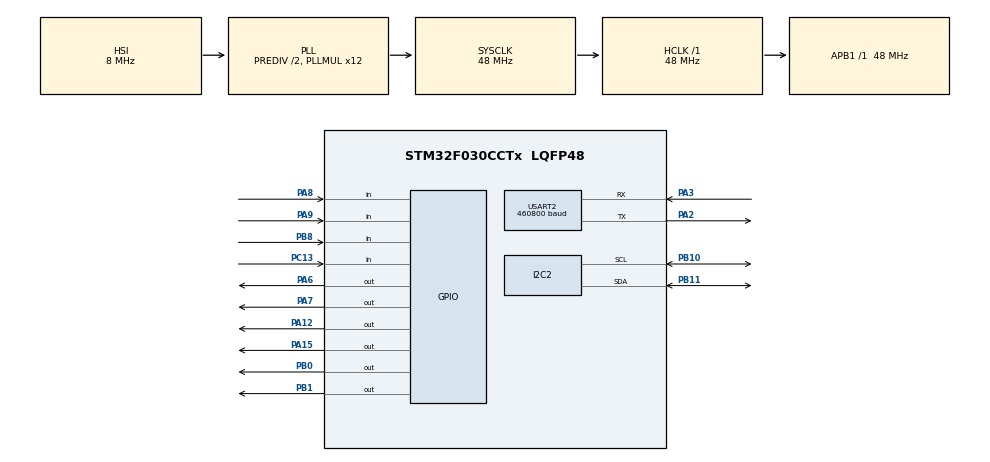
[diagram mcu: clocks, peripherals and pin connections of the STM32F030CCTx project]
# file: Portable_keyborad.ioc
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Dma.I2C2_RX.0.Direction=DMA_PERIPH_TO_MEMORY
Dma.I2C2_RX.0.Instance=DMA1_Channel5
Dma.I2C2_RX.0.MemDataAlignment=DMA_MDATAALIGN_BYTE
Dma.I2C2_RX.0.MemInc=DMA_MINC_ENABLE
Dma.I2C2_RX.0.Mode=DMA_NORMAL
Dma.I2C2_RX.0.PeriphDataAlignment=DMA_PDATAALIGN_BYTE
Dma.I2C2_RX.0.PeriphInc=DMA_PINC_DISABLE
Dma.I2C2_RX.0.Priority=DMA_PRIORITY_LOW
Dma.I2C2_TX.1.Direction=DMA_MEMORY_TO_PERIPH
Dma.I2C2_TX.1.Instance=DMA1_Channel4
Dma.I2C2_TX.1.MemDataAlignment=DMA_MDATAALIGN_BYTE
Dma.I2C2_TX.1.MemInc=DMA_MINC_ENABLE
Dma.I2C2_TX.1.Mode=DMA_NORMAL
Dma.I2C2_TX.1.PeriphDataAlignment=DMA_PDATAALIGN_BYTE
Dma.I2C2_TX.1.PeriphInc=DMA_PINC_DISABLE
Dma.I2C2_TX.1.Priority=DMA_PRIORITY_LOW
Dma.Request0=I2C2_RX
Dma.Request1=I2C2_TX
FREERTOS.Tasks01=defaultTask,0,128,StartDefaultTask,Default,NULL
I2C2.Timing=0x20303E5D
IWDG.Prescaler=IWDG_PRESCALER_32
IWDG.Reload=2000
IWDG.Window=2000
Mcu.Family=STM32F0
Mcu.Name=STM32F030CCTx
Mcu.Package=LQFP48
NVIC.DMA1_Channel4_5_IRQn=true\:3\:0\:false\:false\:true\:true\:false
NVIC.TIM1_BRK_UP_TRG_COM_IRQn=true\:3\:0\:false\:false\:true\:true\:true
PA12.Signal=GPIO_Output
PA13.Mode=Serial_Wire
PA13.Signal=SYS_SWDIO
PA14.Mode=Serial_Wire
PA14.Signal=SYS_SWCLK
PA15.Signal=GPIO_Output
PA2.Mode=Asynchronous
PA2.Signal=USART2_TX
PA3.Mode=Asynchronous
PA3.Signal=USART2_RX
PA6.Signal=GPIO_Output
PA7.Signal=GPIO_Output
PA8.GPIO_PuPd=GPIO_PULLUP
PA8.Signal=GPIO_Input
PA9.GPIO_PuPd=GPIO_PULLUP
PA9.Signal=GPIO_Input
PB0.Signal=GPIO_Output
PB1.Signal=GPIO_Output
PB10.Mode=I2C
PB10.Signal=I2C2_SCL
PB11.Mode=I2C
PB11.Signal=I2C2_SDA
PB8.Signal=GPIO_Input
PC13.GPIO_PuPd=GPIO_PULLUP
PC13.Signal=GPIO_Input
PC14OSC32_IN.GPIO_PuPd=GPIO_PULLUP
PC14OSC32_IN.Signal=GPIO_Input
PC15OSC32_OUT.GPIO_PuPd=GPIO_PULLUP
PC15OSC32_OUT.Signal=GPIO_Input
ProjectManager.HeapSize=0x200
ProjectManager.StackSize=0x400
ProjectManager.TargetToolchain=MDK-ARM V5
RCC.AHBFreq_Value=48000000
RCC.APB1Freq_Value=48000000
RCC.APB1TimFreq_Value=48000000
RCC.HCLKFreq_Value=48000000
RCC.HSE_VALUE=12000000
RCC.PLLDivider=RCC_PREDIV_DIV2
RCC.PLLMUL=RCC_PLL_MUL12
RCC.SYSCLKFreq_VALUE=48000000
RCC.SYSCLKSource=RCC_SYSCLKSOURCE_PLLCLK
TIM1.Period=100-1
TIM1.Prescaler=480
USART2.BaudRate=460800
USART2.VirtualMode-Asynchronous=VM_ASYNC
VP_FREERTOS_VS_ENABLE.Mode=Enabled
VP_IWDG_VS_IWDG.Mode=IWDG_Activate
VP_TIM1_VS_ClockSourceINT.Mode=Internal
board=custom

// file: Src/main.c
/* USER CODE BEGIN Header */
/**
  ******************************************************************************
  * @file           : main.c
  * @brief          : Main program body
  ******************************************************************************
  * This notice applies to any and all portions of this file
  * that are not between comment pairs USER CODE BEGIN and
  * USER CODE END. Other portions of this file, whether
  * inserted by the user or by software development tools
  * are owned by their respective copyright owners.
  *
  * Copyright (c) 2019 STMicroelectronics International N.V.
  * All rights reserved.
  *
  * Redistribution and use in source and binary forms, with or without
  * modification, are permitted, provided that the following conditions are met:
  *
  * 1. Redistribution of source code must retain the above copyright notice,
  *    this list of conditions and the following disclaimer.
  * 2. Redistributions in binary form must reproduce the above copyright notice,
  *    this list of conditions and the following disclaimer in the documentation
  *    and/or other materials provided with the distribution.
  * 3. Neither the name of STMicroelectronics nor the names of other
  *    contributors to this software may be used to endorse or promote products
  *    derived from this software without specific written permission.
  * 4. This software, including modifications and/or derivative works of this
  *    software, must execute solely and exclusively on microcontroller or
  *    microprocessor devices manufactured by or for STMicroelectronics.
  * 5. Redistribution and use of this software other than as permitted under
  *    this license is void and will automatically terminate your rights under
  *    this license.
  *
  * THIS SOFTWARE IS PROVIDED BY STMICROELECTRONICS AND CONTRIBUTORS "AS IS"
  * AND ANY EXPRESS, IMPLIED OR STATUTORY WARRANTIES, INCLUDING, BUT NOT
  * LIMITED TO, THE IMPLIED WARRANTIES OF MERCHANTABILITY, FITNESS FOR A
  * PARTICULAR PURPOSE AND NON-INFRINGEMENT OF THIRD PARTY INTELLECTUAL PROPERTY
  * RIGHTS ARE DISCLAIMED TO THE FULLEST EXTENT PERMITTED BY LAW. IN NO EVENT
  * SHALL STMICROELECTRONICS OR CONTRIBUTORS BE LIABLE FOR ANY DIRECT, INDIRECT,
  * INCIDENTAL, SPECIAL, EXEMPLARY, OR CONSEQUENTIAL DAMAGES (INCLUDING, BUT NOT
  * LIMITED TO, PROCUREMENT OF SUBSTITUTE GOODS OR SERVICES; LOSS OF USE, DATA,
  * OR PROFITS; OR BUSINESS INTERRUPTION) HOWEVER CAUSED AND ON ANY THEORY OF
  * LIABILITY, WHETHER IN CONTRACT, STRICT LIABILITY, OR TORT (INCLUDING
  * NEGLIGENCE OR OTHERWISE) ARISING IN ANY WAY OUT OF THE USE OF THIS SOFTWARE,
  * EVEN IF ADVISED OF THE POSSIBILITY OF SUCH DAMAGE.
  *
  ******************************************************************************
  */
/* USER CODE END Header */

#include "main.h"
#include "cmsis_os.h"

/* USER CODE BEGIN Includes */
#include "task_manager.h"
#include "dev_manager.h"
#include "includes.h"
#include "board.h"
#include "main_task.h"
#include "led.h"
/* USER CODE END Includes */

I2C_HandleTypeDef hi2c2;
DMA_HandleTypeDef hdma_i2c2_rx;
DMA_HandleTypeDef hdma_i2c2_tx;

IWDG_HandleTypeDef hiwdg;

TIM_HandleTypeDef htim1;

UART_HandleTypeDef huart2;

osThreadId defaultTaskHandle;

void SystemClock_Config(void);
static void MX_GPIO_Init(void);
static void MX_DMA_Init(void);
static void MX_USART2_UART_Init(void);
static void MX_I2C2_Init(void);
static void MX_TIM1_Init(void);
static void MX_IWDG_Init(void);
void StartDefaultTask(void const * argument);

/* USER CODE BEGIN PFP */
extern u8  get_cpu_reset_source(void);
extern void board_printf_sys_information(void);
/* USER CODE END PFP */

int main(void)
{

  /* MCU Configuration--------------------------------------------------------*/

  /* Reset of all peripherals, Initializes the Flash interface and the Systick. */
  HAL_Init();

  /* Configure the system clock */
  SystemClock_Config();

  /* Initialize all configured peripherals */
  MX_GPIO_Init();
  MX_DMA_Init();
  MX_USART2_UART_Init();
  MX_I2C2_Init();
  MX_TIM1_Init();
  MX_IWDG_Init();
  /* USER CODE BEGIN 2 */

  board_printf_sys_information();

	main_task_init(NULL);

  /* USER CODE END 2 */

  /* Create the thread(s) */
  /* definition and creation of defaultTask */
  osThreadDef(defaultTask, StartDefaultTask, osPriorityNormal, 0, 32);
  defaultTaskHandle = osThreadCreate(osThread(defaultTask), NULL);

  /* Start scheduler */
  osKernelStart();

  /* We should never get here as control is now taken by the scheduler */

  /* Infinite loop */
  while (1)
  {

  }
}

void SystemClock_Config(void)
{
  RCC_OscInitTypeDef RCC_OscInitStruct = {0};
  RCC_ClkInitTypeDef RCC_ClkInitStruct = {0};

  /**Initializes the CPU, AHB and APB busses clocks
  */
  RCC_OscInitStruct.OscillatorType = RCC_OSCILLATORTYPE_HSI|RCC_OSCILLATORTYPE_LSI;
  RCC_OscInitStruct.HSIState = RCC_HSI_ON;
  RCC_OscInitStruct.HSICalibrationValue = RCC_HSICALIBRATION_DEFAULT;
  RCC_OscInitStruct.LSIState = RCC_LSI_ON;
  RCC_OscInitStruct.PLL.PLLState = RCC_PLL_ON;
  RCC_OscInitStruct.PLL.PLLSource = RCC_PLLSOURCE_HSI;
  RCC_OscInitStruct.PLL.PLLMUL = RCC_PLL_MUL12;
  RCC_OscInitStruct.PLL.PREDIV = RCC_PREDIV_DIV2;
  if (HAL_RCC_OscConfig(&RCC_OscInitStruct) != HAL_OK)
  {
    Error_Handler();
  }
  /**Initializes the CPU, AHB and APB busses clocks
  */
  RCC_ClkInitStruct.ClockType = RCC_CLOCKTYPE_HCLK|RCC_CLOCKTYPE_SYSCLK
                              |RCC_CLOCKTYPE_PCLK1;
  RCC_ClkInitStruct.SYSCLKSource = RCC_SYSCLKSOURCE_PLLCLK;
  RCC_ClkInitStruct.AHBCLKDivider = RCC_SYSCLK_DIV1;
  RCC_ClkInitStruct.APB1CLKDivider = RCC_HCLK_DIV1;

  if (HAL_RCC_ClockConfig(&RCC_ClkInitStruct, FLASH_LATENCY_1) != HAL_OK)
  {
    Error_Handler();
  }
}

static void MX_I2C2_Init(void)
{

  hi2c2.Instance = I2C2;
  hi2c2.Init.Timing = 0x20303E5D;
  hi2c2.Init.OwnAddress1 = 0;
  hi2c2.Init.AddressingMode = I2C_ADDRESSINGMODE_7BIT;
  hi2c2.Init.DualAddressMode = I2C_DUALADDRESS_DISABLE;
  hi2c2.Init.OwnAddress2 = 0;
  hi2c2.Init.OwnAddress2Masks = I2C_OA2_NOMASK;
  hi2c2.Init.GeneralCallMode = I2C_GENERALCALL_DISABLE;
  hi2c2.Init.NoStretchMode = I2C_NOSTRETCH_DISABLE;
  if (HAL_I2C_Init(&hi2c2) != HAL_OK)
  {
    Error_Handler();
  }
  /**Configure Analogue filter
  */
  if (HAL_I2CEx_ConfigAnalogFilter(&hi2c2, I2C_ANALOGFILTER_ENABLE) != HAL_OK)
  {
    Error_Handler();
  }
  /**Configure Digital filter
  */
  if (HAL_I2CEx_ConfigDigitalFilter(&hi2c2, 0) != HAL_OK)
  {
    Error_Handler();
  }

}

static void MX_IWDG_Init(void)
{

  hiwdg.Instance = IWDG;
  hiwdg.Init.Prescaler = IWDG_PRESCALER_32;
  hiwdg.Init.Window = 2000;
  hiwdg.Init.Reload = 2000;
  if (HAL_IWDG_Init(&hiwdg) != HAL_OK)
  {
    Error_Handler();
  }

}

static void MX_TIM1_Init(void)
{

  TIM_ClockConfigTypeDef sClockSourceConfig = {0};
  TIM_MasterConfigTypeDef sMasterConfig = {0};

  htim1.Instance = TIM1;
  htim1.Init.Prescaler = 480;
  htim1.Init.CounterMode = TIM_COUNTERMODE_UP;
  htim1.Init.Period = 100-1;
  htim1.Init.ClockDivision = TIM_CLOCKDIVISION_DIV1;
  htim1.Init.RepetitionCounter = 0;
  htim1.Init.AutoReloadPreload = TIM_AUTORELOAD_PRELOAD_DISABLE;
  if (HAL_TIM_Base_Init(&htim1) != HAL_OK)
  {
    Error_Handler();
  }
  sClockSourceConfig.ClockSource = TIM_CLOCKSOURCE_INTERNAL;
  if (HAL_TIM_ConfigClockSource(&htim1, &sClockSourceConfig) != HAL_OK)
  {
    Error_Handler();
  }
  sMasterConfig.MasterOutputTrigger = TIM_TRGO_RESET;
  sMasterConfig.MasterSlaveMode = TIM_MASTERSLAVEMODE_DISABLE;
  if (HAL_TIMEx_MasterConfigSynchronization(&htim1, &sMasterConfig) != HAL_OK)
  {
    Error_Handler();
  }
  /* USER CODE BEGIN TIM1_Init 2 */
//  HAL_TIM_Base_Start_IT(&htim1);
  /* USER CODE END TIM1_Init 2 */

}

static void MX_USART2_UART_Init(void)
{

  huart2.Instance = USART2;
  huart2.Init.BaudRate = 460800;
  huart2.Init.WordLength = UART_WORDLENGTH_8B;
  huart2.Init.StopBits = UART_STOPBITS_1;
  huart2.Init.Parity = UART_PARITY_NONE;
  huart2.Init.Mode = UART_MODE_TX_RX;
  huart2.Init.HwFlowCtl = UART_HWCONTROL_NONE;
  huart2.Init.OverSampling = UART_OVERSAMPLING_16;
  huart2.Init.OneBitSampling = UART_ONE_BIT_SAMPLE_DISABLE;
  huart2.AdvancedInit.AdvFeatureInit = UART_ADVFEATURE_NO_INIT;
  if (HAL_UART_Init(&huart2) != HAL_OK)
  {
    Error_Handler();
  }

}

static void MX_DMA_Init(void)
{
  /* DMA controller clock enable */
  __HAL_RCC_DMA1_CLK_ENABLE();

  /* DMA interrupt init */
  /* DMA1_Channel4_5_IRQn interrupt configuration */
  HAL_NVIC_SetPriority(DMA1_Channel4_5_IRQn, 3, 0);
  HAL_NVIC_EnableIRQ(DMA1_Channel4_5_IRQn);

}

static void MX_GPIO_Init(void)
{
  GPIO_InitTypeDef GPIO_InitStruct = {0};

  /* GPIO Ports Clock Enable */
  __HAL_RCC_GPIOC_CLK_ENABLE();
  __HAL_RCC_GPIOA_CLK_ENABLE();
  __HAL_RCC_GPIOB_CLK_ENABLE();

  /*Configure GPIO pin Output Level */
  HAL_GPIO_WritePin(GPIOA, GPIO_PIN_6|GPIO_PIN_7|GPIO_PIN_12|GPIO_PIN_15, GPIO_PIN_RESET);

  /*Configure GPIO pin Output Level */
  HAL_GPIO_WritePin(GPIOB, GPIO_PIN_0|GPIO_PIN_1, GPIO_PIN_RESET);

  /*Configure GPIO pins : PC13 PC14 PC15 */
  GPIO_InitStruct.Pin = GPIO_PIN_13|GPIO_PIN_14|GPIO_PIN_15;
  GPIO_InitStruct.Mode = GPIO_MODE_INPUT;
  GPIO_InitStruct.Pull = GPIO_PULLUP;
  HAL_GPIO_Init(GPIOC, &GPIO_InitStruct);

  /*Configure GPIO pins : PA6 PA7 PA12 PA15 */
  GPIO_InitStruct.Pin = GPIO_PIN_6|GPIO_PIN_7|GPIO_PIN_12|GPIO_PIN_15;
  GPIO_InitStruct.Mode = GPIO_MODE_OUTPUT_PP;
  GPIO_InitStruct.Pull = GPIO_NOPULL;
  GPIO_InitStruct.Speed = GPIO_SPEED_FREQ_LOW;
  HAL_GPIO_Init(GPIOA, &GPIO_InitStruct);

  /*Configure GPIO pins : PB0 PB1 */
  GPIO_InitStruct.Pin = GPIO_PIN_0|GPIO_PIN_1;
  GPIO_InitStruct.Mode = GPIO_MODE_OUTPUT_PP;
  GPIO_InitStruct.Pull = GPIO_NOPULL;
  GPIO_InitStruct.Speed = GPIO_SPEED_FREQ_LOW;
  HAL_GPIO_Init(GPIOB, &GPIO_InitStruct);

  /*Configure GPIO pins : PA8 PA9 */
  GPIO_InitStruct.Pin = GPIO_PIN_8|GPIO_PIN_9;
  GPIO_InitStruct.Mode = GPIO_MODE_INPUT;
  GPIO_InitStruct.Pull = GPIO_PULLUP;
  HAL_GPIO_Init(GPIOA, &GPIO_InitStruct);

  /*Configure GPIO pin : PB8 */
  GPIO_InitStruct.Pin = GPIO_PIN_8;
  GPIO_InitStruct.Mode = GPIO_MODE_INPUT;
  GPIO_InitStruct.Pull = GPIO_PULLUP;
  HAL_GPIO_Init(GPIOB, &GPIO_InitStruct);

}

/* USER CODE BEGIN 4 */
int fputc(int ch, FILE *f)
{
	while((DBUG_UART->ISR&0X40)==0);//ѭ������,ֱ���������
	DBUG_UART->TDR = (u8) ch;
	return ch;
}
/* USER CODE END 4 */

void StartDefaultTask(void const * argument)
{

  /* USER CODE BEGIN 5 */

  /* Infinite loop */
  for(;;)
  {

    HAL_IWDG_Refresh(&hiwdg);
		osDelay(1000);
  }
  /* USER CODE END 5 */
}

void Error_Handler(void)
{
  /* USER CODE BEGIN Error_Handler_Debug */
  /* User can add his own implementation to report the HAL error return state */
	ASSERT(0);
  /* USER CODE END Error_Handler_Debug */
}

/************************ (C) COPYRIGHT STMicroelectronics *****END OF FILE****/
